VERSION 5.8 ;
BUSBITCHARS "[]" ;
DIVIDERCHAR "/" ;
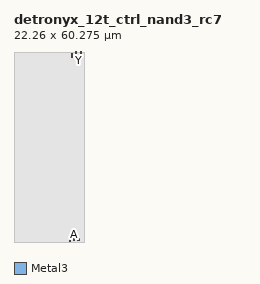
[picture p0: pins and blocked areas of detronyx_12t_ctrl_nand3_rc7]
MACRO detronyx_12t_ctrl_nand3_rc7
  CLASS BLOCK ;
  FOREIGN detronyx_12t_ctrl_nand3_rc7 0.000 0.000 ;
  ORIGIN 0.000 0.000 ;
  SIZE 22.260000 BY 60.275000 ;
  SYMMETRY X Y ;
  PIN VDD
    DIRECTION INOUT ;
    USE POWER ;
    PORT
      LAYER Metal3 ;
        RECT 18.180000 58.575000 18.540000 59.775000 ;
    END
  END VDD
  PIN VSS
    DIRECTION INOUT ;
    USE GROUND ;
    PORT
      LAYER Metal3 ;
        RECT 17.480000 0.200000 17.840000 1.400000 ;
    END
  END VSS
  PIN A
    DIRECTION INPUT ;
    USE SIGNAL ;
    PORT
      LAYER Metal3 ;
        RECT 18.880000 0.400000 19.240000 1.200000 ;
    END
  END A
  PIN B
    DIRECTION INPUT ;
    USE SIGNAL ;
    PORT
      LAYER Metal3 ;
        RECT 19.580000 59.675000 19.940000 60.475000 ;
    END
  END B
  PIN C
    DIRECTION INPUT ;
    USE SIGNAL ;
    PORT
      LAYER Metal3 ;
        RECT 20.280000 0.400000 20.640000 1.200000 ;
    END
  END C
  PIN Y
    DIRECTION OUTPUT ;
    USE SIGNAL ;
    PORT
      LAYER Metal3 ;
        RECT 20.980000 59.675000 21.340000 60.475000 ;
    END
  END Y
  OBS
    LAYER Metal1 ;
      RECT 0.000000 0.000000 22.260000 60.275000 ;
    LAYER Metal2 ;
      RECT 0.000000 0.000000 22.260000 60.275000 ;
  END
END detronyx_12t_ctrl_nand3_rc7
END LIBRARY
